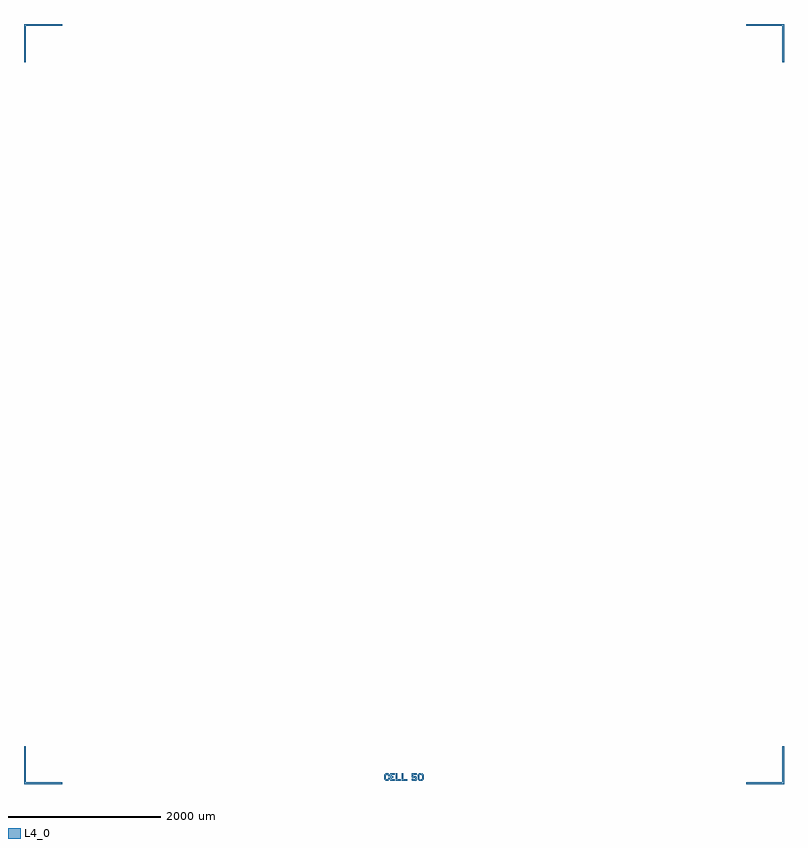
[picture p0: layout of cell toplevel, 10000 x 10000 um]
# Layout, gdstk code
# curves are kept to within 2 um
import gdstk
lib = gdstk.Library(unit=1e-6, precision=1e-09)
def P(c, l, *ps):  # polygons
    for p in ps: c.add(gdstk.Polygon(p, *l))
L4_0 = (4, 0)

toplevel = lib.new_cell('toplevel')
P(toplevel, L4_0, [(5000,5000),(5000,4500),(4980,4500),(4980,4980),(4500,4980),(4500,5000)],
  [(-5000,5000),(-5000,4500),(-4980,4500),(-4980,4980),(-4500,4980),(-4500,5000)],
  [(5000,-5000),(5000,-4500),(4980,-4500),(4980,-4980),(4500,-4980),(4500,-5000)],
  [(-5000,-5000),(-5000,-4500),(-4980,-4500),(-4980,-4980),(-4500,-4980),(-4500,-5000)],
  [(-240,-4960),(-260,-4940),(-260,-4880),(-240,-4860),(-210,-4860),(-190,-4880),(-190,-4900),(-210,-4900),(-210,-4890),(-220,-4880),(-230,-4880),(-240,-4890),(-240,-4930),(-230,-4940),(-220,-4940),(-210,-4930),(-210,-4920),(-190,-4920),(-190,-4940),(-210,-4960)],
  [(-120,-4860),(-120,-4880),(-160,-4880),(-160,-4900),(-140,-4900),(-140,-4920),(-160,-4920),(-160,-4940),(-120,-4940),(-120,-4960),(-180,-4960),(-180,-4860),(-120,-4860)],
  [(-110,-4860),(-90,-4860),(-90,-4940),(-40,-4940),(-40,-4960),(-110,-4960),(-110,-4860)],
  [(-30,-4860),(-10,-4860),(-10,-4940),(40,-4940),(40,-4960),(-30,-4960),(-30,-4860)],
  [(170,-4880),(120,-4880),(120,-4900),(160,-4900),(170,-4910),(170,-4950),(160,-4960),(110,-4960),(100,-4950),(100,-4930),(120,-4930),(120,-4940),(150,-4940),(150,-4920),(110,-4920),(100,-4910),(100,-4860),(170,-4860)],
  [(210,-4880),(200,-4890),(200,-4930),(210,-4940),(205,-4960),(200,-4960),(180,-4940),(180,-4880),(200,-4860),(223,-4860),(218,-4880),(210,-4880)],
  [(230,-4940),(240,-4930),(240,-4890),(230,-4880),(235,-4860),(240,-4860),(260,-4880),(260,-4940),(240,-4960),(217,-4960),(222,-4940),(230,-4940)])

lib.write_gds('toplevel.gds')
